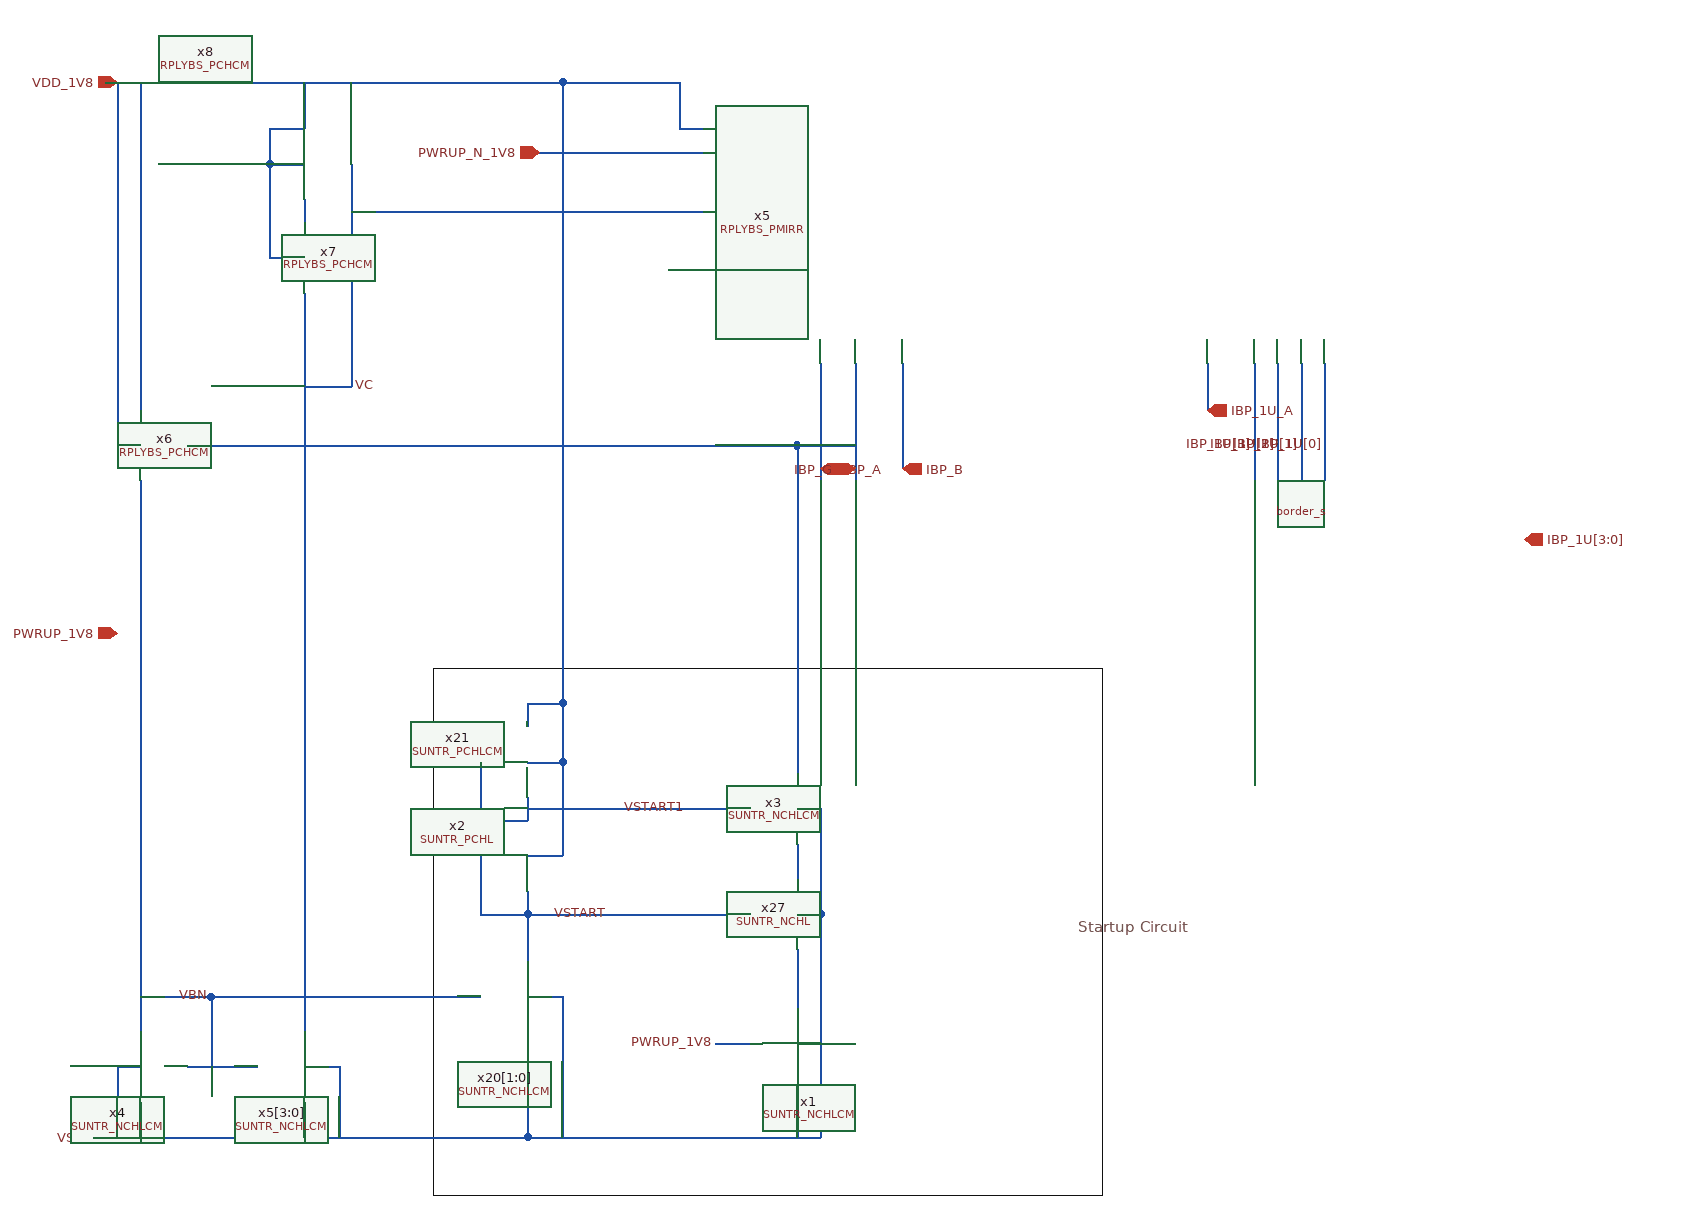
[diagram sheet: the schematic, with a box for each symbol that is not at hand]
v {xschem version=3.1.0 file_version=1.2 }
G {}
K {}
V {}
S {}
E {}
L 3 -320 -340 250 -340 {}
L 3 -320 -340 -320 110 {}
L 3 250 -340 250 110 {}
L 3 -320 110 250 110 {}
T {Startup Circuit} 230 -130 0 1 0.4 0.4 {}
N -340 -840 -290 -840 {
lab=VDD_1V8}
N -600 -840 -340 -840 {
lab=VDD_1V8}
N -610 60 -370 60 {
lab=VSS}
N -570 -840 -570 -560 {
lab=VDD_1V8}
N -590 -530 -570 -530 {
lab=VDD_1V8}
N -590 -840 -590 -530 {
lab=VDD_1V8}
N -460 -770 -430 -770 {
lab=VDD_1V8}
N -460 -800 -460 -770 {
lab=VDD_1V8}
N -460 -800 -430 -800 {
lab=VDD_1V8}
N -430 -840 -430 -800 {
lab=VDD_1V8}
N -570 -500 -570 -30 {
lab=VBN}
N -590 -0 -570 -0 {
lab=VSS}
N -590 -0 -590 60 {
lab=VSS}
N -570 30 -570 60 {
lab=VSS}
N -430 30 -430 60 {
lab=VSS}
N -430 0 -400 0 {
lab=VSS}
N -400 0 -400 60 {
lab=VSS}
N -530 0 -470 0 {
lab=VBN}
N -430 -740 -430 -720 {
lab=#net1}
N -430 -590 -430 -30 {
lab=VC}
N -430 -580 -390 -580 {
lab=VC}
N -390 -610 -390 -580 {
lab=VC}
N -390 -690 -390 -610 {
lab=VC}
N -390 -770 -390 -690 {
lab=VC}
N -570 -60 -510 -60 {
lab=VBN}
N -510 -60 -510 0 {
lab=VBN}
N -430 -600 -430 -590 {
lab=VC}
N 440 -600 440 -500 {
lab=IBP_1U[0]}
N 420 -600 420 -500 {
lab=IBP_1U[1]}
N 400 -600 400 -500 {
lab=IBP_1U[2]}
N 380 -600 380 -500 {
lab=IBP_1U[3]}
N 10 30 10 60 {
lab=VSS}
N -230 60 -40 60 {
lab=VSS}
N -40 60 10 60 {
lab=VSS}
N -240 -60 -210 -60 {
lab=VSS}
N -210 -60 -210 60 {
lab=VSS}
N -240 -30 -240 60 {
lab=VSS}
N -240 -260 -210 -260 {
lab=VDD_1V8}
N -210 -310 -210 -260 {
lab=VDD_1V8}
N -240 -310 -240 -290 {
lab=VDD_1V8}
N -240 -140 -240 -120 {
lab=VSTART}
N -240 -130 -200 -130 {
lab=VSTART}
N -10 -130 10 -130 {
lab=VSS}
N 10 -130 10 30 {
lab=VSS}
N -10 -190 -10 -160 {
lab=#net2}
N -200 -130 -50 -130 {
lab=VSTART}
N -10 -100 -10 -50 {
lab=#net3}
N -10 -20 10 -20 {
lab=VSS}
N -10 10 -10 60 {
lab=VSS}
N -80 -20 -50 -20 {
lab=PWRUP_1V8}
N -240 -310 -210 -310 {
lab=VDD_1V8}
N -280 -260 -280 -210 {
lab=VSTART1}
N -280 -210 -240 -210 {
lab=VSTART1}
N -240 -230 -240 -210 {
lab=VSTART1}
N -240 -180 -210 -180 {
lab=VDD_1V8}
N -210 -260 -210 -180 {
lab=VDD_1V8}
N -280 -180 -280 -130 {
lab=VSTART}
N -280 -130 -240 -130 {
lab=VSTART}
N -240 -150 -240 -130 {
lab=VSTART}
N -240 -140 -240 -130 {
lab=VSTART}
N -10 -220 10 -220 {
lab=VSS}
N 10 -220 10 -130 {
lab=VSS}
N -160 -220 -50 -220 {
lab=VSTART1}
N -240 -220 -190 -220 {
lab=VSTART1}
N -240 -120 -240 -90 {
lab=VSTART}
N -510 -60 -280 -60 {
lab=VBN}
N -240 60 -230 60 {
lab=VSS}
N -370 60 -240 60 {
lab=VSS}
N -210 -840 -210 -310 {
lab=VDD_1V8}
N -460 -690 -430 -690 {
lab=VDD_1V8}
N -460 -770 -460 -690 {
lab=VDD_1V8}
N -430 -660 -430 -600 {
lab=VC}
N -190 -220 -160 -220 {
lab=VSTART1}
N 40 -600 40 -500 {
lab=IBP_G}
N 10 -600 10 -500 {
lab=IBP_A}
N 80 -600 80 -510 {
lab=IBP_B}
N 340 -600 340 -560 {
lab=IBP_1U_A}
N -390 -730 -90 -730 {
lab=VC}
N -120 -680 -90 -680 {
lab=#net4}
N -110 -800 -90 -800 {
lab=VDD_1V8}
N -110 -840 -110 -800 {
lab=VDD_1V8}
N -230 -780 -90 -780 {
lab=PWRUP_N_1V8}
N -210 -840 -110 -840 {
lab=VDD_1V8}
N -290 -840 -210 -840 {
lab=VDD_1V8}
N -10 -530 40 -530 {
lab=IBP_G}
N -530 -530 -10 -530 {
lab=IBP_G}
N -10 -530 -10 -250 {
lab=IBP_G}
C {cborder/border_s.sym} 510 0 0 0 {
user="Carsten Wulff"
company="Carsten Wulff Software"}
C {devices/ipin.sym} -590 -840 0 0 {name=p1 lab=VDD_1V8}
C {devices/ipin.sym} -600 60 0 0 {name=p2 lab=VSS}
C {devices/opin.sym} 610 -450 1 0 {name=p8 lab=IBP_1U[3:0]}
C {SUN_TR_SKY130NM/SUNTR_NCHLCM.sym} -530 0 0 1 {name=x4 }
C {SUN_TR_SKY130NM/SUNTR_NCHLCM.sym} -470 0 0 0 {name=x5[3:0] }
C {devices/lab_pin.sym} -390 -580 0 1 {name=l12 sig_type=std_logic lab=VC}
C {devices/lab_wire.sym} 440 -530 1 1 {name=l11 sig_type=std_logic lab=IBP_1U[0]}
C {devices/lab_wire.sym} 420 -530 1 1 {name=l14 sig_type=std_logic lab=IBP_1U[1]}
C {devices/lab_wire.sym} 400 -530 1 1 {name=l15 sig_type=std_logic lab=IBP_1U[2]}
C {devices/lab_wire.sym} 380 -530 1 1 {name=l16 sig_type=std_logic lab=IBP_1U[3]}
C {devices/opin.sym} 340 -560 1 0 {name=p3 lab=IBP_1U_A}
C {devices/opin.sym} 10 -510 1 0 {name=p5 lab=IBP_A}
C {devices/opin.sym} 80 -510 1 0 {name=p6 lab=IBP_B}
C {devices/ipin.sym} 40 -510 3 0 {name=p7 lab=IBP_G}
C {devices/lab_pin.sym} -80 -20 0 0 {name=l8 sig_type=std_logic lab=PWRUP_1V8}
C {SUN_TR_SKY130NM/SUNTR_NCHLCM.sym} -280 -60 0 0 {name=x20[1:0]  }
C {SUN_TR_SKY130NM/SUNTR_PCHLCM.sym} -280 -260 0 0 {name=x21  }
C {SUN_TR_SKY130NM/SUNTR_NCHL.sym} -50 -130 0 0 {name=x27  }
C {devices/lab_wire.sym} -220 -130 0 1 {name=l1 sig_type=std_logic lab=VSTART}
C {SUN_TR_SKY130NM/SUNTR_NCHLCM.sym} -50 -20 0 0 {name=x1  }
C {SUN_TR_SKY130NM/SUNTR_PCHL.sym} -280 -180 0 0 {name=x2  }
C {SUN_TR_SKY130NM/SUNTR_NCHLCM.sym} -50 -220 0 0 {name=x3  }
C {devices/ipin.sym} -590 -370 0 0 {name=p9 lab=PWRUP_1V8}
C {devices/ipin.sym} -230 -780 0 0 {name=p10 lab=PWRUP_N_1V8}
C {devices/lab_wire.sym} -540 -60 0 1 {name=l2 sig_type=std_logic lab=VBN}
C {devices/lab_wire.sym} -160 -220 0 1 {name=l3 sig_type=std_logic lab=VSTART1}
C {RPLY_BIAS_SKY130NM/RPLYBS_PMIRR.sym} -70 -810 0 0 {name=x5 }
C {RPLY_BIAS_SKY130NM/RPLYBS_PCHCM.sym} -530 -530 0 1 {name=x6 }
C {RPLY_BIAS_SKY130NM/RPLYBS_PCHCM.sym} -390 -690 0 1 {name=x7 }
C {RPLY_BIAS_SKY130NM/RPLYBS_PCHCM.sym} -390 -770 0 1 {name=x8 }
